VERSION 5.7 ;
  NOWIREEXTENSIONATPIN ON ;
  DIVIDERCHAR "/" ;
  BUSBITCHARS "[]" ;
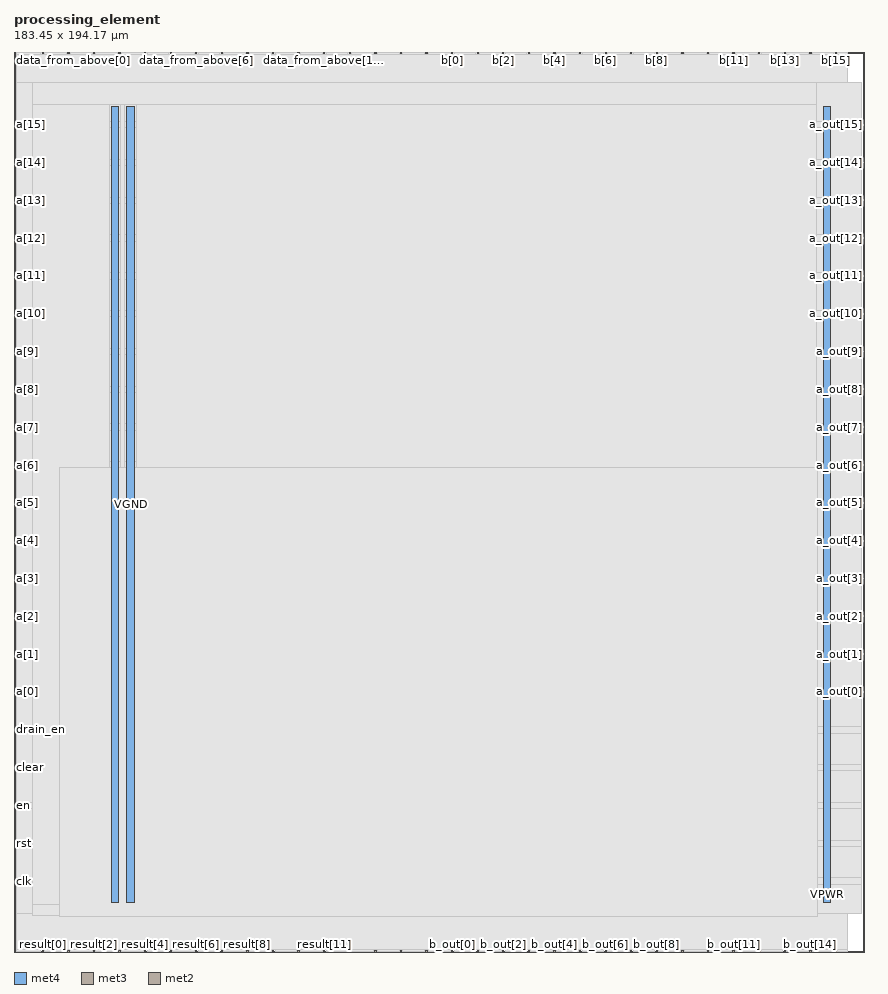
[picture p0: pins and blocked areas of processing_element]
MACRO processing_element
  CLASS BLOCK ;
  FOREIGN processing_element ;
  ORIGIN 0.000 0.000 ;
  SIZE 183.450 BY 194.170 ;
  PIN VGND
    DIRECTION INOUT ;
    USE GROUND ;
    PORT
      LAYER met4 ;
        RECT 24.340 10.640 25.940 182.480 ;
    END
  END VGND
  PIN VPWR
    DIRECTION INOUT ;
    USE POWER ;
    PORT
      LAYER met4 ;
        RECT 21.040 10.640 22.640 182.480 ;
    END
    PORT
      LAYER met4 ;
        RECT 174.640 10.640 176.240 182.480 ;
    END
  END VPWR
  PIN a[0]
    DIRECTION INPUT ;
    USE SIGNAL ;
    ANTENNAGATEAREA 0.196500 ;
    PORT
      LAYER met3 ;
        RECT 0.000 55.800 0.600 56.400 ;
    END
  END a[0]
  PIN a[10]
    DIRECTION INPUT ;
    USE SIGNAL ;
    ANTENNAGATEAREA 0.196500 ;
    PORT
      LAYER met3 ;
        RECT 0.000 137.400 0.600 138.000 ;
    END
  END a[10]
  PIN a[11]
    DIRECTION INPUT ;
    USE SIGNAL ;
    ANTENNAGATEAREA 0.196500 ;
    PORT
      LAYER met3 ;
        RECT 0.000 145.560 0.600 146.160 ;
    END
  END a[11]
  PIN a[12]
    DIRECTION INPUT ;
    USE SIGNAL ;
    ANTENNAGATEAREA 0.196500 ;
    PORT
      LAYER met3 ;
        RECT 0.000 153.720 0.600 154.320 ;
    END
  END a[12]
  PIN a[13]
    DIRECTION INPUT ;
    USE SIGNAL ;
    ANTENNAGATEAREA 0.196500 ;
    PORT
      LAYER met3 ;
        RECT 0.000 161.880 0.600 162.480 ;
    END
  END a[13]
  PIN a[14]
    DIRECTION INPUT ;
    USE SIGNAL ;
    ANTENNAGATEAREA 0.196500 ;
    PORT
      LAYER met3 ;
        RECT 0.000 170.040 0.600 170.640 ;
    END
  END a[14]
  PIN a[15]
    DIRECTION INPUT ;
    USE SIGNAL ;
    ANTENNAGATEAREA 0.196500 ;
    PORT
      LAYER met3 ;
        RECT 0.000 178.200 0.600 178.800 ;
    END
  END a[15]
  PIN a[1]
    DIRECTION INPUT ;
    USE SIGNAL ;
    ANTENNAGATEAREA 0.196500 ;
    PORT
      LAYER met3 ;
        RECT 0.000 63.960 0.600 64.560 ;
    END
  END a[1]
  PIN a[2]
    DIRECTION INPUT ;
    USE SIGNAL ;
    ANTENNAGATEAREA 0.196500 ;
    PORT
      LAYER met3 ;
        RECT 0.000 72.120 0.600 72.720 ;
    END
  END a[2]
  PIN a[3]
    DIRECTION INPUT ;
    USE SIGNAL ;
    ANTENNAGATEAREA 0.196500 ;
    PORT
      LAYER met3 ;
        RECT 0.000 80.280 0.600 80.880 ;
    END
  END a[3]
  PIN a[4]
    DIRECTION INPUT ;
    USE SIGNAL ;
    ANTENNAGATEAREA 0.196500 ;
    PORT
      LAYER met3 ;
        RECT 0.000 88.440 0.600 89.040 ;
    END
  END a[4]
  PIN a[5]
    DIRECTION INPUT ;
    USE SIGNAL ;
    ANTENNAGATEAREA 0.196500 ;
    PORT
      LAYER met3 ;
        RECT 0.000 96.600 0.600 97.200 ;
    END
  END a[5]
  PIN a[6]
    DIRECTION INPUT ;
    USE SIGNAL ;
    ANTENNAGATEAREA 0.196500 ;
    PORT
      LAYER met3 ;
        RECT 0.000 104.760 0.600 105.360 ;
    END
  END a[6]
  PIN a[7]
    DIRECTION INPUT ;
    USE SIGNAL ;
    ANTENNAGATEAREA 0.196500 ;
    PORT
      LAYER met3 ;
        RECT 0.000 112.920 0.600 113.520 ;
    END
  END a[7]
  PIN a[8]
    DIRECTION INPUT ;
    USE SIGNAL ;
    ANTENNAGATEAREA 0.196500 ;
    PORT
      LAYER met3 ;
        RECT 0.000 121.080 0.600 121.680 ;
    END
  END a[8]
  PIN a[9]
    DIRECTION INPUT ;
    USE SIGNAL ;
    ANTENNAGATEAREA 0.196500 ;
    PORT
      LAYER met3 ;
        RECT 0.000 129.240 0.600 129.840 ;
    END
  END a[9]
  PIN a_out[0]
    DIRECTION OUTPUT ;
    USE SIGNAL ;
    ANTENNADIFFAREA 0.795200 ;
    PORT
      LAYER met3 ;
        RECT 182.850 55.800 183.450 56.400 ;
    END
  END a_out[0]
  PIN a_out[10]
    DIRECTION OUTPUT ;
    USE SIGNAL ;
    ANTENNADIFFAREA 0.795200 ;
    PORT
      LAYER met3 ;
        RECT 182.850 137.400 183.450 138.000 ;
    END
  END a_out[10]
  PIN a_out[11]
    DIRECTION OUTPUT ;
    USE SIGNAL ;
    ANTENNADIFFAREA 0.795200 ;
    PORT
      LAYER met3 ;
        RECT 182.850 145.560 183.450 146.160 ;
    END
  END a_out[11]
  PIN a_out[12]
    DIRECTION OUTPUT ;
    USE SIGNAL ;
    ANTENNADIFFAREA 0.795200 ;
    PORT
      LAYER met3 ;
        RECT 182.850 153.720 183.450 154.320 ;
    END
  END a_out[12]
  PIN a_out[13]
    DIRECTION OUTPUT ;
    USE SIGNAL ;
    ANTENNADIFFAREA 0.795200 ;
    PORT
      LAYER met3 ;
        RECT 182.850 161.880 183.450 162.480 ;
    END
  END a_out[13]
  PIN a_out[14]
    DIRECTION OUTPUT ;
    USE SIGNAL ;
    ANTENNADIFFAREA 0.795200 ;
    PORT
      LAYER met3 ;
        RECT 182.850 170.040 183.450 170.640 ;
    END
  END a_out[14]
  PIN a_out[15]
    DIRECTION OUTPUT ;
    USE SIGNAL ;
    ANTENNADIFFAREA 0.795200 ;
    PORT
      LAYER met3 ;
        RECT 182.850 178.200 183.450 178.800 ;
    END
  END a_out[15]
  PIN a_out[1]
    DIRECTION OUTPUT ;
    USE SIGNAL ;
    ANTENNADIFFAREA 0.795200 ;
    PORT
      LAYER met3 ;
        RECT 182.850 63.960 183.450 64.560 ;
    END
  END a_out[1]
  PIN a_out[2]
    DIRECTION OUTPUT ;
    USE SIGNAL ;
    ANTENNADIFFAREA 0.795200 ;
    PORT
      LAYER met3 ;
        RECT 182.850 72.120 183.450 72.720 ;
    END
  END a_out[2]
  PIN a_out[3]
    DIRECTION OUTPUT ;
    USE SIGNAL ;
    ANTENNADIFFAREA 0.795200 ;
    PORT
      LAYER met3 ;
        RECT 182.850 80.280 183.450 80.880 ;
    END
  END a_out[3]
  PIN a_out[4]
    DIRECTION OUTPUT ;
    USE SIGNAL ;
    ANTENNADIFFAREA 0.795200 ;
    PORT
      LAYER met3 ;
        RECT 182.850 88.440 183.450 89.040 ;
    END
  END a_out[4]
  PIN a_out[5]
    DIRECTION OUTPUT ;
    USE SIGNAL ;
    ANTENNADIFFAREA 0.795200 ;
    PORT
      LAYER met3 ;
        RECT 182.850 96.600 183.450 97.200 ;
    END
  END a_out[5]
  PIN a_out[6]
    DIRECTION OUTPUT ;
    USE SIGNAL ;
    ANTENNADIFFAREA 0.795200 ;
    PORT
      LAYER met3 ;
        RECT 182.850 104.760 183.450 105.360 ;
    END
  END a_out[6]
  PIN a_out[7]
    DIRECTION OUTPUT ;
    USE SIGNAL ;
    ANTENNADIFFAREA 0.795200 ;
    PORT
      LAYER met3 ;
        RECT 182.850 112.920 183.450 113.520 ;
    END
  END a_out[7]
  PIN a_out[8]
    DIRECTION OUTPUT ;
    USE SIGNAL ;
    ANTENNADIFFAREA 0.795200 ;
    PORT
      LAYER met3 ;
        RECT 182.850 121.080 183.450 121.680 ;
    END
  END a_out[8]
  PIN a_out[9]
    DIRECTION OUTPUT ;
    USE SIGNAL ;
    ANTENNADIFFAREA 0.795200 ;
    PORT
      LAYER met3 ;
        RECT 182.850 129.240 183.450 129.840 ;
    END
  END a_out[9]
  PIN b[0]
    DIRECTION INPUT ;
    USE SIGNAL ;
    ANTENNAGATEAREA 0.196500 ;
    PORT
      LAYER met2 ;
        RECT 94.390 193.890 94.670 194.170 ;
    END
  END b[0]
  PIN b[10]
    DIRECTION INPUT ;
    USE SIGNAL ;
    ANTENNAGATEAREA 0.631200 ;
    ANTENNADIFFAREA 0.434700 ;
    PORT
      LAYER met2 ;
        RECT 149.590 193.890 149.870 194.170 ;
    END
  END b[10]
  PIN b[11]
    DIRECTION INPUT ;
    USE SIGNAL ;
    ANTENNAGATEAREA 0.196500 ;
    PORT
      LAYER met2 ;
        RECT 155.110 193.890 155.390 194.170 ;
    END
  END b[11]
  PIN b[12]
    DIRECTION INPUT ;
    USE SIGNAL ;
    ANTENNAGATEAREA 0.196500 ;
    PORT
      LAYER met2 ;
        RECT 160.630 193.890 160.910 194.170 ;
    END
  END b[12]
  PIN b[13]
    DIRECTION INPUT ;
    USE SIGNAL ;
    ANTENNAGATEAREA 0.631200 ;
    ANTENNADIFFAREA 0.434700 ;
    PORT
      LAYER met2 ;
        RECT 166.150 193.890 166.430 194.170 ;
    END
  END b[13]
  PIN b[14]
    DIRECTION INPUT ;
    USE SIGNAL ;
    ANTENNAGATEAREA 0.631200 ;
    ANTENNADIFFAREA 0.434700 ;
    PORT
      LAYER met2 ;
        RECT 171.670 193.890 171.950 194.170 ;
    END
  END b[14]
  PIN b[15]
    DIRECTION INPUT ;
    USE SIGNAL ;
    ANTENNAGATEAREA 0.631200 ;
    ANTENNADIFFAREA 0.434700 ;
    PORT
      LAYER met2 ;
        RECT 177.190 193.890 177.470 194.170 ;
    END
  END b[15]
  PIN b[1]
    DIRECTION INPUT ;
    USE SIGNAL ;
    ANTENNAGATEAREA 0.196500 ;
    PORT
      LAYER met2 ;
        RECT 99.910 193.890 100.190 194.170 ;
    END
  END b[1]
  PIN b[2]
    DIRECTION INPUT ;
    USE SIGNAL ;
    ANTENNAGATEAREA 0.196500 ;
    PORT
      LAYER met2 ;
        RECT 105.430 193.890 105.710 194.170 ;
    END
  END b[2]
  PIN b[3]
    DIRECTION INPUT ;
    USE SIGNAL ;
    ANTENNAGATEAREA 0.196500 ;
    PORT
      LAYER met2 ;
        RECT 110.950 193.890 111.230 194.170 ;
    END
  END b[3]
  PIN b[4]
    DIRECTION INPUT ;
    USE SIGNAL ;
    ANTENNAGATEAREA 0.196500 ;
    PORT
      LAYER met2 ;
        RECT 116.470 193.890 116.750 194.170 ;
    END
  END b[4]
  PIN b[5]
    DIRECTION INPUT ;
    USE SIGNAL ;
    ANTENNAGATEAREA 0.196500 ;
    PORT
      LAYER met2 ;
        RECT 121.990 193.890 122.270 194.170 ;
    END
  END b[5]
  PIN b[6]
    DIRECTION INPUT ;
    USE SIGNAL ;
    ANTENNAGATEAREA 0.196500 ;
    PORT
      LAYER met2 ;
        RECT 127.510 193.890 127.790 194.170 ;
    END
  END b[6]
  PIN b[7]
    DIRECTION INPUT ;
    USE SIGNAL ;
    ANTENNAGATEAREA 0.196500 ;
    PORT
      LAYER met2 ;
        RECT 133.030 193.890 133.310 194.170 ;
    END
  END b[7]
  PIN b[8]
    DIRECTION INPUT ;
    USE SIGNAL ;
    ANTENNAGATEAREA 0.196500 ;
    PORT
      LAYER met2 ;
        RECT 138.550 193.890 138.830 194.170 ;
    END
  END b[8]
  PIN b[9]
    DIRECTION INPUT ;
    USE SIGNAL ;
    ANTENNAGATEAREA 0.196500 ;
    PORT
      LAYER met2 ;
        RECT 144.070 193.890 144.350 194.170 ;
    END
  END b[9]
  PIN b_out[0]
    DIRECTION OUTPUT ;
    USE SIGNAL ;
    ANTENNADIFFAREA 0.795200 ;
    PORT
      LAYER met2 ;
        RECT 94.390 0.000 94.670 0.280 ;
    END
  END b_out[0]
  PIN b_out[10]
    DIRECTION OUTPUT ;
    USE SIGNAL ;
    ANTENNADIFFAREA 0.795200 ;
    PORT
      LAYER met2 ;
        RECT 149.590 0.000 149.870 0.280 ;
    END
  END b_out[10]
  PIN b_out[11]
    DIRECTION OUTPUT ;
    USE SIGNAL ;
    ANTENNADIFFAREA 0.795200 ;
    PORT
      LAYER met2 ;
        RECT 155.110 0.000 155.390 0.280 ;
    END
  END b_out[11]
  PIN b_out[12]
    DIRECTION OUTPUT ;
    USE SIGNAL ;
    ANTENNADIFFAREA 0.795200 ;
    PORT
      LAYER met2 ;
        RECT 160.630 0.000 160.910 0.280 ;
    END
  END b_out[12]
  PIN b_out[13]
    DIRECTION OUTPUT ;
    USE SIGNAL ;
    ANTENNADIFFAREA 0.795200 ;
    PORT
      LAYER met2 ;
        RECT 166.150 0.000 166.430 0.280 ;
    END
  END b_out[13]
  PIN b_out[14]
    DIRECTION OUTPUT ;
    USE SIGNAL ;
    ANTENNADIFFAREA 0.795200 ;
    PORT
      LAYER met2 ;
        RECT 171.670 0.000 171.950 0.280 ;
    END
  END b_out[14]
  PIN b_out[15]
    DIRECTION OUTPUT ;
    USE SIGNAL ;
    ANTENNADIFFAREA 0.795200 ;
    PORT
      LAYER met2 ;
        RECT 177.190 0.000 177.470 0.280 ;
    END
  END b_out[15]
  PIN b_out[1]
    DIRECTION OUTPUT ;
    USE SIGNAL ;
    ANTENNADIFFAREA 0.795200 ;
    PORT
      LAYER met2 ;
        RECT 99.910 0.000 100.190 0.280 ;
    END
  END b_out[1]
  PIN b_out[2]
    DIRECTION OUTPUT ;
    USE SIGNAL ;
    ANTENNADIFFAREA 0.795200 ;
    PORT
      LAYER met2 ;
        RECT 105.430 0.000 105.710 0.280 ;
    END
  END b_out[2]
  PIN b_out[3]
    DIRECTION OUTPUT ;
    USE SIGNAL ;
    ANTENNADIFFAREA 0.795200 ;
    PORT
      LAYER met2 ;
        RECT 110.950 0.000 111.230 0.280 ;
    END
  END b_out[3]
  PIN b_out[4]
    DIRECTION OUTPUT ;
    USE SIGNAL ;
    ANTENNADIFFAREA 0.795200 ;
    PORT
      LAYER met2 ;
        RECT 116.470 0.000 116.750 0.280 ;
    END
  END b_out[4]
  PIN b_out[5]
    DIRECTION OUTPUT ;
    USE SIGNAL ;
    ANTENNADIFFAREA 0.795200 ;
    PORT
      LAYER met2 ;
        RECT 121.990 0.000 122.270 0.280 ;
    END
  END b_out[5]
  PIN b_out[6]
    DIRECTION OUTPUT ;
    USE SIGNAL ;
    ANTENNADIFFAREA 0.795200 ;
    PORT
      LAYER met2 ;
        RECT 127.510 0.000 127.790 0.280 ;
    END
  END b_out[6]
  PIN b_out[7]
    DIRECTION OUTPUT ;
    USE SIGNAL ;
    ANTENNADIFFAREA 0.795200 ;
    PORT
      LAYER met2 ;
        RECT 133.030 0.000 133.310 0.280 ;
    END
  END b_out[7]
  PIN b_out[8]
    DIRECTION OUTPUT ;
    USE SIGNAL ;
    ANTENNADIFFAREA 0.795200 ;
    PORT
      LAYER met2 ;
        RECT 138.550 0.000 138.830 0.280 ;
    END
  END b_out[8]
  PIN b_out[9]
    DIRECTION OUTPUT ;
    USE SIGNAL ;
    ANTENNADIFFAREA 0.795200 ;
    PORT
      LAYER met2 ;
        RECT 144.070 0.000 144.350 0.280 ;
    END
  END b_out[9]
  PIN clear
    DIRECTION INPUT ;
    USE SIGNAL ;
    ANTENNAGATEAREA 0.196500 ;
    PORT
      LAYER met3 ;
        RECT 0.000 39.480 0.600 40.080 ;
    END
  END clear
  PIN clk
    DIRECTION INPUT ;
    USE SIGNAL ;
    ANTENNAGATEAREA 0.852000 ;
    PORT
      LAYER met3 ;
        RECT 0.000 15.000 0.600 15.600 ;
    END
  END clk
  PIN data_from_above[0]
    DIRECTION INPUT ;
    USE SIGNAL ;
    ANTENNAGATEAREA 0.196500 ;
    PORT
      LAYER met2 ;
        RECT 6.070 193.890 6.350 194.170 ;
    END
  END data_from_above[0]
  PIN data_from_above[10]
    DIRECTION INPUT ;
    USE SIGNAL ;
    ANTENNAGATEAREA 0.196500 ;
    PORT
      LAYER met2 ;
        RECT 61.270 193.890 61.550 194.170 ;
    END
  END data_from_above[10]
  PIN data_from_above[11]
    DIRECTION INPUT ;
    USE SIGNAL ;
    ANTENNAGATEAREA 0.196500 ;
    PORT
      LAYER met2 ;
        RECT 66.790 193.890 67.070 194.170 ;
    END
  END data_from_above[11]
  PIN data_from_above[12]
    DIRECTION INPUT ;
    USE SIGNAL ;
    ANTENNAGATEAREA 0.196500 ;
    PORT
      LAYER met2 ;
        RECT 72.310 193.890 72.590 194.170 ;
    END
  END data_from_above[12]
  PIN data_from_above[13]
    DIRECTION INPUT ;
    USE SIGNAL ;
    ANTENNAGATEAREA 0.196500 ;
    PORT
      LAYER met2 ;
        RECT 77.830 193.890 78.110 194.170 ;
    END
  END data_from_above[13]
  PIN data_from_above[14]
    DIRECTION INPUT ;
    USE SIGNAL ;
    ANTENNAGATEAREA 0.196500 ;
    PORT
      LAYER met2 ;
        RECT 83.350 193.890 83.630 194.170 ;
    END
  END data_from_above[14]
  PIN data_from_above[15]
    DIRECTION INPUT ;
    USE SIGNAL ;
    ANTENNAGATEAREA 0.196500 ;
    PORT
      LAYER met2 ;
        RECT 88.870 193.890 89.150 194.170 ;
    END
  END data_from_above[15]
  PIN data_from_above[1]
    DIRECTION INPUT ;
    USE SIGNAL ;
    ANTENNAGATEAREA 0.196500 ;
    PORT
      LAYER met2 ;
        RECT 11.590 193.890 11.870 194.170 ;
    END
  END data_from_above[1]
  PIN data_from_above[2]
    DIRECTION INPUT ;
    USE SIGNAL ;
    ANTENNAGATEAREA 0.196500 ;
    PORT
      LAYER met2 ;
        RECT 17.110 193.890 17.390 194.170 ;
    END
  END data_from_above[2]
  PIN data_from_above[3]
    DIRECTION INPUT ;
    USE SIGNAL ;
    ANTENNAGATEAREA 0.196500 ;
    PORT
      LAYER met2 ;
        RECT 22.630 193.890 22.910 194.170 ;
    END
  END data_from_above[3]
  PIN data_from_above[4]
    DIRECTION INPUT ;
    USE SIGNAL ;
    ANTENNAGATEAREA 0.196500 ;
    PORT
      LAYER met2 ;
        RECT 28.150 193.890 28.430 194.170 ;
    END
  END data_from_above[4]
  PIN data_from_above[5]
    DIRECTION INPUT ;
    USE SIGNAL ;
    ANTENNAGATEAREA 0.196500 ;
    PORT
      LAYER met2 ;
        RECT 33.670 193.890 33.950 194.170 ;
    END
  END data_from_above[5]
  PIN data_from_above[6]
    DIRECTION INPUT ;
    USE SIGNAL ;
    ANTENNAGATEAREA 0.196500 ;
    PORT
      LAYER met2 ;
        RECT 39.190 193.890 39.470 194.170 ;
    END
  END data_from_above[6]
  PIN data_from_above[7]
    DIRECTION INPUT ;
    USE SIGNAL ;
    ANTENNAGATEAREA 0.196500 ;
    PORT
      LAYER met2 ;
        RECT 44.710 193.890 44.990 194.170 ;
    END
  END data_from_above[7]
  PIN data_from_above[8]
    DIRECTION INPUT ;
    USE SIGNAL ;
    ANTENNAGATEAREA 0.196500 ;
    PORT
      LAYER met2 ;
        RECT 50.230 193.890 50.510 194.170 ;
    END
  END data_from_above[8]
  PIN data_from_above[9]
    DIRECTION INPUT ;
    USE SIGNAL ;
    ANTENNAGATEAREA 0.196500 ;
    PORT
      LAYER met2 ;
        RECT 55.750 193.890 56.030 194.170 ;
    END
  END data_from_above[9]
  PIN drain_en
    DIRECTION INPUT ;
    USE SIGNAL ;
    ANTENNAGATEAREA 0.196500 ;
    PORT
      LAYER met3 ;
        RECT 0.000 47.640 0.600 48.240 ;
    END
  END drain_en
  PIN en
    DIRECTION INPUT ;
    USE SIGNAL ;
    ANTENNAGATEAREA 0.196500 ;
    PORT
      LAYER met3 ;
        RECT 0.000 31.320 0.600 31.920 ;
    END
  END en
  PIN result[0]
    DIRECTION OUTPUT ;
    USE SIGNAL ;
    ANTENNADIFFAREA 0.795200 ;
    PORT
      LAYER met2 ;
        RECT 6.070 0.000 6.350 0.280 ;
    END
  END result[0]
  PIN result[10]
    DIRECTION OUTPUT ;
    USE SIGNAL ;
    ANTENNADIFFAREA 0.795200 ;
    PORT
      LAYER met2 ;
        RECT 61.270 0.000 61.550 0.280 ;
    END
  END result[10]
  PIN result[11]
    DIRECTION OUTPUT ;
    USE SIGNAL ;
    ANTENNADIFFAREA 0.795200 ;
    PORT
      LAYER met2 ;
        RECT 66.790 0.000 67.070 0.280 ;
    END
  END result[11]
  PIN result[12]
    DIRECTION OUTPUT ;
    USE SIGNAL ;
    ANTENNADIFFAREA 0.795200 ;
    PORT
      LAYER met2 ;
        RECT 72.310 0.000 72.590 0.280 ;
    END
  END result[12]
  PIN result[13]
    DIRECTION OUTPUT ;
    USE SIGNAL ;
    ANTENNADIFFAREA 0.795200 ;
    PORT
      LAYER met2 ;
        RECT 77.830 0.000 78.110 0.280 ;
    END
  END result[13]
  PIN result[14]
    DIRECTION OUTPUT ;
    USE SIGNAL ;
    ANTENNADIFFAREA 0.795200 ;
    PORT
      LAYER met2 ;
        RECT 83.350 0.000 83.630 0.280 ;
    END
  END result[14]
  PIN result[15]
    DIRECTION OUTPUT ;
    USE SIGNAL ;
    ANTENNADIFFAREA 0.795200 ;
    PORT
      LAYER met2 ;
        RECT 88.870 0.000 89.150 0.280 ;
    END
  END result[15]
  PIN result[1]
    DIRECTION OUTPUT ;
    USE SIGNAL ;
    ANTENNADIFFAREA 0.795200 ;
    PORT
      LAYER met2 ;
        RECT 11.590 0.000 11.870 0.280 ;
    END
  END result[1]
  PIN result[2]
    DIRECTION OUTPUT ;
    USE SIGNAL ;
    ANTENNADIFFAREA 0.795200 ;
    PORT
      LAYER met2 ;
        RECT 17.110 0.000 17.390 0.280 ;
    END
  END result[2]
  PIN result[3]
    DIRECTION OUTPUT ;
    USE SIGNAL ;
    ANTENNADIFFAREA 0.795200 ;
    PORT
      LAYER met2 ;
        RECT 22.630 0.000 22.910 0.280 ;
    END
  END result[3]
  PIN result[4]
    DIRECTION OUTPUT ;
    USE SIGNAL ;
    ANTENNADIFFAREA 0.795200 ;
    PORT
      LAYER met2 ;
        RECT 28.150 0.000 28.430 0.280 ;
    END
  END result[4]
  PIN result[5]
    DIRECTION OUTPUT ;
    USE SIGNAL ;
    ANTENNADIFFAREA 0.795200 ;
    PORT
      LAYER met2 ;
        RECT 33.670 0.000 33.950 0.280 ;
    END
  END result[5]
  PIN result[6]
    DIRECTION OUTPUT ;
    USE SIGNAL ;
    ANTENNADIFFAREA 0.795200 ;
    PORT
      LAYER met2 ;
        RECT 39.190 0.000 39.470 0.280 ;
    END
  END result[6]
  PIN result[7]
    DIRECTION OUTPUT ;
    USE SIGNAL ;
    ANTENNADIFFAREA 0.795200 ;
    PORT
      LAYER met2 ;
        RECT 44.710 0.000 44.990 0.280 ;
    END
  END result[7]
  PIN result[8]
    DIRECTION OUTPUT ;
    USE SIGNAL ;
    ANTENNADIFFAREA 0.795200 ;
    PORT
      LAYER met2 ;
        RECT 50.230 0.000 50.510 0.280 ;
    END
  END result[8]
  PIN result[9]
    DIRECTION OUTPUT ;
    USE SIGNAL ;
    ANTENNADIFFAREA 0.795200 ;
    PORT
      LAYER met2 ;
        RECT 55.750 0.000 56.030 0.280 ;
    END
  END result[9]
  PIN rst
    DIRECTION INPUT ;
    USE SIGNAL ;
    ANTENNAGATEAREA 0.196500 ;
    PORT
      LAYER met3 ;
        RECT 0.000 23.160 0.600 23.760 ;
    END
  END rst
  OBS
      LAYER nwell ;
        RECT 5.330 10.795 177.750 182.430 ;
      LAYER li1 ;
        RECT 5.520 10.795 177.560 182.325 ;
      LAYER met1 ;
        RECT 0.530 8.540 179.790 194.100 ;
      LAYER met2 ;
        RECT 0.550 193.610 5.790 194.130 ;
        RECT 6.630 193.610 11.310 194.130 ;
        RECT 12.150 193.610 16.830 194.130 ;
        RECT 17.670 193.610 22.350 194.130 ;
        RECT 23.190 193.610 27.870 194.130 ;
        RECT 28.710 193.610 33.390 194.130 ;
        RECT 34.230 193.610 38.910 194.130 ;
        RECT 39.750 193.610 44.430 194.130 ;
        RECT 45.270 193.610 49.950 194.130 ;
        RECT 50.790 193.610 55.470 194.130 ;
        RECT 56.310 193.610 60.990 194.130 ;
        RECT 61.830 193.610 66.510 194.130 ;
        RECT 67.350 193.610 72.030 194.130 ;
        RECT 72.870 193.610 77.550 194.130 ;
        RECT 78.390 193.610 83.070 194.130 ;
        RECT 83.910 193.610 88.590 194.130 ;
        RECT 89.430 193.610 94.110 194.130 ;
        RECT 94.950 193.610 99.630 194.130 ;
        RECT 100.470 193.610 105.150 194.130 ;
        RECT 105.990 193.610 110.670 194.130 ;
        RECT 111.510 193.610 116.190 194.130 ;
        RECT 117.030 193.610 121.710 194.130 ;
        RECT 122.550 193.610 127.230 194.130 ;
        RECT 128.070 193.610 132.750 194.130 ;
        RECT 133.590 193.610 138.270 194.130 ;
        RECT 139.110 193.610 143.790 194.130 ;
        RECT 144.630 193.610 149.310 194.130 ;
        RECT 150.150 193.610 154.830 194.130 ;
        RECT 155.670 193.610 160.350 194.130 ;
        RECT 161.190 193.610 165.870 194.130 ;
        RECT 166.710 193.610 171.390 194.130 ;
        RECT 172.230 193.610 176.910 194.130 ;
        RECT 177.750 193.610 179.760 194.130 ;
        RECT 0.550 0.560 179.760 193.610 ;
        RECT 0.550 0.070 5.790 0.560 ;
        RECT 6.630 0.070 11.310 0.560 ;
        RECT 12.150 0.070 16.830 0.560 ;
        RECT 17.670 0.070 22.350 0.560 ;
        RECT 23.190 0.070 27.870 0.560 ;
        RECT 28.710 0.070 33.390 0.560 ;
        RECT 34.230 0.070 38.910 0.560 ;
        RECT 39.750 0.070 44.430 0.560 ;
        RECT 45.270 0.070 49.950 0.560 ;
        RECT 50.790 0.070 55.470 0.560 ;
        RECT 56.310 0.070 60.990 0.560 ;
        RECT 61.830 0.070 66.510 0.560 ;
        RECT 67.350 0.070 72.030 0.560 ;
        RECT 72.870 0.070 77.550 0.560 ;
        RECT 78.390 0.070 83.070 0.560 ;
        RECT 83.910 0.070 88.590 0.560 ;
        RECT 89.430 0.070 94.110 0.560 ;
        RECT 94.950 0.070 99.630 0.560 ;
        RECT 100.470 0.070 105.150 0.560 ;
        RECT 105.990 0.070 110.670 0.560 ;
        RECT 111.510 0.070 116.190 0.560 ;
        RECT 117.030 0.070 121.710 0.560 ;
        RECT 122.550 0.070 127.230 0.560 ;
        RECT 128.070 0.070 132.750 0.560 ;
        RECT 133.590 0.070 138.270 0.560 ;
        RECT 139.110 0.070 143.790 0.560 ;
        RECT 144.630 0.070 149.310 0.560 ;
        RECT 150.150 0.070 154.830 0.560 ;
        RECT 155.670 0.070 160.350 0.560 ;
        RECT 161.190 0.070 165.870 0.560 ;
        RECT 166.710 0.070 171.390 0.560 ;
        RECT 172.230 0.070 176.910 0.560 ;
        RECT 177.750 0.070 179.760 0.560 ;
      LAYER met3 ;
        RECT 0.600 179.200 182.850 187.505 ;
        RECT 1.000 177.800 182.450 179.200 ;
        RECT 0.600 171.040 182.850 177.800 ;
        RECT 1.000 169.640 182.450 171.040 ;
        RECT 0.600 162.880 182.850 169.640 ;
        RECT 1.000 161.480 182.450 162.880 ;
        RECT 0.600 154.720 182.850 161.480 ;
        RECT 1.000 153.320 182.450 154.720 ;
        RECT 0.600 146.560 182.850 153.320 ;
        RECT 1.000 145.160 182.450 146.560 ;
        RECT 0.600 138.400 182.850 145.160 ;
        RECT 1.000 137.000 182.450 138.400 ;
        RECT 0.600 130.240 182.850 137.000 ;
        RECT 1.000 128.840 182.450 130.240 ;
        RECT 0.600 122.080 182.850 128.840 ;
        RECT 1.000 120.680 182.450 122.080 ;
        RECT 0.600 113.920 182.850 120.680 ;
        RECT 1.000 112.520 182.450 113.920 ;
        RECT 0.600 105.760 182.850 112.520 ;
        RECT 1.000 104.360 182.450 105.760 ;
        RECT 0.600 97.600 182.850 104.360 ;
        RECT 1.000 96.200 182.450 97.600 ;
        RECT 0.600 89.440 182.850 96.200 ;
        RECT 1.000 88.040 182.450 89.440 ;
        RECT 0.600 81.280 182.850 88.040 ;
        RECT 1.000 79.880 182.450 81.280 ;
        RECT 0.600 73.120 182.850 79.880 ;
        RECT 1.000 71.720 182.450 73.120 ;
        RECT 0.600 64.960 182.850 71.720 ;
        RECT 1.000 63.560 182.450 64.960 ;
        RECT 0.600 56.800 182.850 63.560 ;
        RECT 1.000 55.400 182.450 56.800 ;
        RECT 0.600 48.640 182.850 55.400 ;
        RECT 1.000 47.240 182.850 48.640 ;
        RECT 0.600 40.480 182.850 47.240 ;
        RECT 1.000 39.080 182.850 40.480 ;
        RECT 0.600 32.320 182.850 39.080 ;
        RECT 1.000 30.920 182.850 32.320 ;
        RECT 0.600 24.160 182.850 30.920 ;
        RECT 1.000 22.760 182.850 24.160 ;
        RECT 0.600 16.000 182.850 22.760 ;
        RECT 1.000 14.600 182.850 16.000 ;
        RECT 0.600 8.335 182.850 14.600 ;
      LAYER met4 ;
        RECT 3.975 182.880 173.090 187.505 ;
        RECT 3.975 10.240 20.640 182.880 ;
        RECT 23.040 10.240 23.940 182.880 ;
        RECT 26.340 10.240 173.090 182.880 ;
        RECT 3.975 7.910 173.090 10.240 ;
      LAYER met5 ;
        RECT 9.780 7.700 173.300 104.500 ;
  END
END processing_element
END LIBRARY

